VERSION 5.8 ;
BUSBITCHARS "[]" ;
DIVIDERCHAR "/" ;
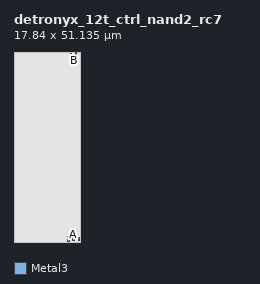
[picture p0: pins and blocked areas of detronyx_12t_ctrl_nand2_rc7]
MACRO detronyx_12t_ctrl_nand2_rc7
  CLASS BLOCK ;
  FOREIGN detronyx_12t_ctrl_nand2_rc7 0.000 0.000 ;
  ORIGIN 0.000 0.000 ;
  SIZE 17.840000 BY 51.135000 ;
  SYMMETRY X Y ;
  PIN VDD
    DIRECTION INOUT ;
    USE POWER ;
    PORT
      LAYER Metal3 ;
        RECT 15.160000 49.435000 15.520000 50.635000 ;
    END
  END VDD
  PIN VSS
    DIRECTION INOUT ;
    USE GROUND ;
    PORT
      LAYER Metal3 ;
        RECT 14.460000 0.200000 14.820000 1.400000 ;
    END
  END VSS
  PIN A
    DIRECTION INPUT ;
    USE SIGNAL ;
    PORT
      LAYER Metal3 ;
        RECT 15.860000 0.400000 16.220000 1.200000 ;
    END
  END A
  PIN B
    DIRECTION INPUT ;
    USE SIGNAL ;
    PORT
      LAYER Metal3 ;
        RECT 16.560000 50.535000 16.920000 51.335000 ;
    END
  END B
  PIN Y
    DIRECTION OUTPUT ;
    USE SIGNAL ;
    PORT
      LAYER Metal3 ;
        RECT 17.260000 0.400000 17.620000 1.200000 ;
    END
  END Y
  OBS
    LAYER Metal1 ;
      RECT 0.000000 0.000000 17.840000 51.135000 ;
    LAYER Metal2 ;
      RECT 0.000000 0.000000 17.840000 51.135000 ;
  END
END detronyx_12t_ctrl_nand2_rc7
END LIBRARY
